VERSION 5.7 ;
  NOWIREEXTENSIONATPIN ON ;
  DIVIDERCHAR "/" ;
  BUSBITCHARS "[]" ;
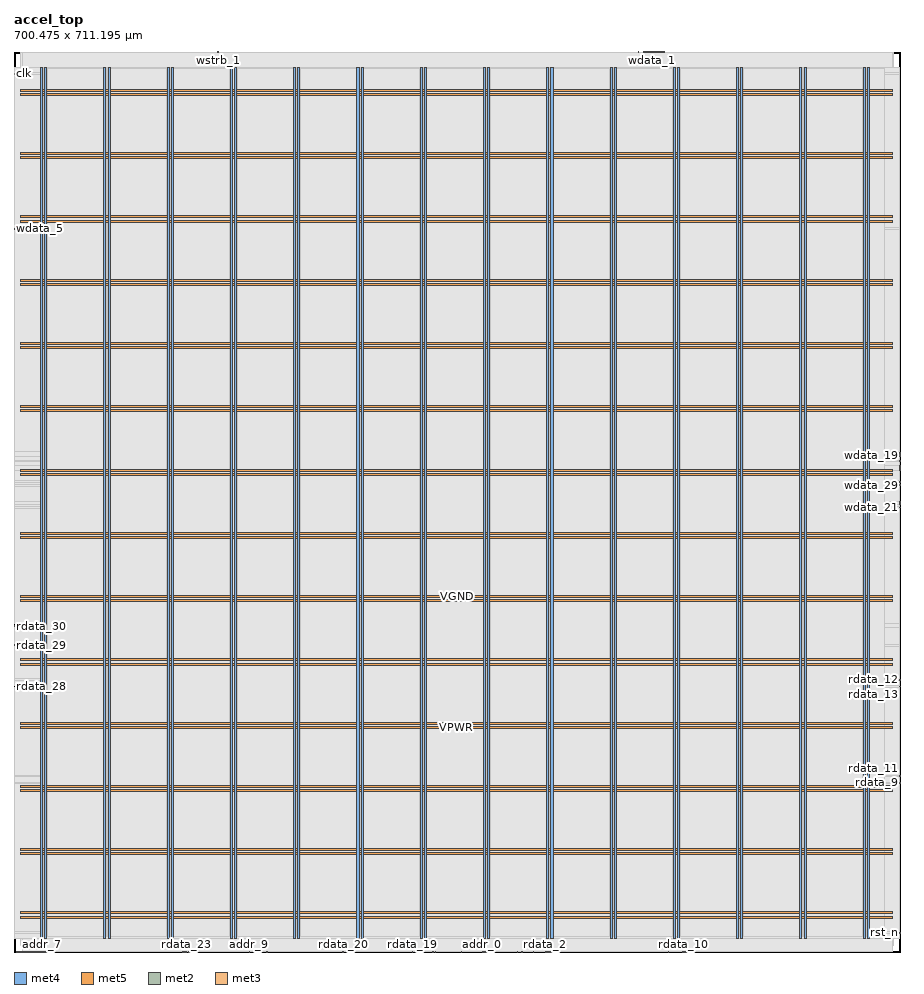
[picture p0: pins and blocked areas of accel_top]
MACRO accel_top
  CLASS BLOCK ;
  FOREIGN accel_top ;
  ORIGIN 0.000 0.000 ;
  SIZE 700.475 BY 711.195 ;
  PIN VGND
    DIRECTION INOUT ;
    USE GROUND ;
    PORT
      LAYER met4 ;
        RECT 24.340 10.640 25.940 699.280 ;
    END
    PORT
      LAYER met4 ;
        RECT 74.340 10.640 75.940 699.280 ;
    END
    PORT
      LAYER met4 ;
        RECT 124.340 10.640 125.940 699.280 ;
    END
    PORT
      LAYER met4 ;
        RECT 174.340 10.640 175.940 699.280 ;
    END
    PORT
      LAYER met4 ;
        RECT 224.340 10.640 225.940 699.280 ;
    END
    PORT
      LAYER met4 ;
        RECT 274.340 10.640 275.940 699.280 ;
    END
    PORT
      LAYER met4 ;
        RECT 324.340 10.640 325.940 699.280 ;
    END
    PORT
      LAYER met4 ;
        RECT 374.340 10.640 375.940 699.280 ;
    END
    PORT
      LAYER met4 ;
        RECT 424.340 10.640 425.940 699.280 ;
    END
    PORT
      LAYER met4 ;
        RECT 474.340 10.640 475.940 699.280 ;
    END
    PORT
      LAYER met4 ;
        RECT 524.340 10.640 525.940 699.280 ;
    END
    PORT
      LAYER met4 ;
        RECT 574.340 10.640 575.940 699.280 ;
    END
    PORT
      LAYER met4 ;
        RECT 624.340 10.640 625.940 699.280 ;
    END
    PORT
      LAYER met4 ;
        RECT 674.340 10.640 675.940 699.280 ;
    END
    PORT
      LAYER met5 ;
        RECT 5.520 30.030 694.600 31.630 ;
    END
    PORT
      LAYER met5 ;
        RECT 5.520 80.030 694.600 81.630 ;
    END
    PORT
      LAYER met5 ;
        RECT 5.520 130.030 694.600 131.630 ;
    END
    PORT
      LAYER met5 ;
        RECT 5.520 180.030 694.600 181.630 ;
    END
    PORT
      LAYER met5 ;
        RECT 5.520 230.030 694.600 231.630 ;
    END
    PORT
      LAYER met5 ;
        RECT 5.520 280.030 694.600 281.630 ;
    END
    PORT
      LAYER met5 ;
        RECT 5.520 330.030 694.600 331.630 ;
    END
    PORT
      LAYER met5 ;
        RECT 5.520 380.030 694.600 381.630 ;
    END
    PORT
      LAYER met5 ;
        RECT 5.520 430.030 694.600 431.630 ;
    END
    PORT
      LAYER met5 ;
        RECT 5.520 480.030 694.600 481.630 ;
    END
    PORT
      LAYER met5 ;
        RECT 5.520 530.030 694.600 531.630 ;
    END
    PORT
      LAYER met5 ;
        RECT 5.520 580.030 694.600 581.630 ;
    END
    PORT
      LAYER met5 ;
        RECT 5.520 630.030 694.600 631.630 ;
    END
    PORT
      LAYER met5 ;
        RECT 5.520 680.030 694.600 681.630 ;
    END
  END VGND
  PIN VPWR
    DIRECTION INOUT ;
    USE POWER ;
    PORT
      LAYER met4 ;
        RECT 21.040 10.640 22.640 699.280 ;
    END
    PORT
      LAYER met4 ;
        RECT 71.040 10.640 72.640 699.280 ;
    END
    PORT
      LAYER met4 ;
        RECT 121.040 10.640 122.640 699.280 ;
    END
    PORT
      LAYER met4 ;
        RECT 171.040 10.640 172.640 699.280 ;
    END
    PORT
      LAYER met4 ;
        RECT 221.040 10.640 222.640 699.280 ;
    END
    PORT
      LAYER met4 ;
        RECT 271.040 10.640 272.640 699.280 ;
    END
    PORT
      LAYER met4 ;
        RECT 321.040 10.640 322.640 699.280 ;
    END
    PORT
      LAYER met4 ;
        RECT 371.040 10.640 372.640 699.280 ;
    END
    PORT
      LAYER met4 ;
        RECT 421.040 10.640 422.640 699.280 ;
    END
    PORT
      LAYER met4 ;
        RECT 471.040 10.640 472.640 699.280 ;
    END
    PORT
      LAYER met4 ;
        RECT 521.040 10.640 522.640 699.280 ;
    END
    PORT
      LAYER met4 ;
        RECT 571.040 10.640 572.640 699.280 ;
    END
    PORT
      LAYER met4 ;
        RECT 621.040 10.640 622.640 699.280 ;
    END
    PORT
      LAYER met4 ;
        RECT 671.040 10.640 672.640 699.280 ;
    END
    PORT
      LAYER met5 ;
        RECT 5.520 26.730 694.600 28.330 ;
    END
    PORT
      LAYER met5 ;
        RECT 5.520 76.730 694.600 78.330 ;
    END
    PORT
      LAYER met5 ;
        RECT 5.520 126.730 694.600 128.330 ;
    END
    PORT
      LAYER met5 ;
        RECT 5.520 176.730 694.600 178.330 ;
    END
    PORT
      LAYER met5 ;
        RECT 5.520 226.730 694.600 228.330 ;
    END
    PORT
      LAYER met5 ;
        RECT 5.520 276.730 694.600 278.330 ;
    END
    PORT
      LAYER met5 ;
        RECT 5.520 326.730 694.600 328.330 ;
    END
    PORT
      LAYER met5 ;
        RECT 5.520 376.730 694.600 378.330 ;
    END
    PORT
      LAYER met5 ;
        RECT 5.520 426.730 694.600 428.330 ;
    END
    PORT
      LAYER met5 ;
        RECT 5.520 476.730 694.600 478.330 ;
    END
    PORT
      LAYER met5 ;
        RECT 5.520 526.730 694.600 528.330 ;
    END
    PORT
      LAYER met5 ;
        RECT 5.520 576.730 694.600 578.330 ;
    END
    PORT
      LAYER met5 ;
        RECT 5.520 626.730 694.600 628.330 ;
    END
    PORT
      LAYER met5 ;
        RECT 5.520 676.730 694.600 678.330 ;
    END
  END VPWR
  PIN addr_0
    DIRECTION INPUT ;
    USE SIGNAL ;
    ANTENNAGATEAREA 1.424700 ;
    ANTENNADIFFAREA 0.434700 ;
    PORT
      LAYER met2 ;
        RECT 369.930 0.000 370.210 0.280 ;
    END
  END addr_0
  PIN addr_1
    DIRECTION INPUT ;
    USE SIGNAL ;
    ANTENNAGATEAREA 0.929700 ;
    ANTENNADIFFAREA 0.434700 ;
    PORT
      LAYER met2 ;
        RECT 370.850 0.000 371.130 0.280 ;
    END
  END addr_1
  PIN addr_10
    DIRECTION INPUT ;
    USE SIGNAL ;
    ANTENNAGATEAREA 0.647700 ;
    ANTENNADIFFAREA 0.434700 ;
    PORT
      LAYER met2 ;
        RECT 371.770 0.000 372.050 0.280 ;
    END
  END addr_10
  PIN addr_11
    DIRECTION INPUT ;
    USE SIGNAL ;
    ANTENNAGATEAREA 0.647700 ;
    ANTENNADIFFAREA 0.434700 ;
    PORT
      LAYER met2 ;
        RECT 372.690 0.000 372.970 0.280 ;
    END
  END addr_11
  PIN addr_12
    DIRECTION INPUT ;
    USE SIGNAL ;
    PORT
      LAYER met2 ;
        RECT 1.930 0.000 2.210 0.280 ;
    END
  END addr_12
  PIN addr_13
    DIRECTION INPUT ;
    USE SIGNAL ;
    PORT
      LAYER met2 ;
        RECT 2.850 0.000 3.130 0.280 ;
    END
  END addr_13
  PIN addr_14
    DIRECTION INPUT ;
    USE SIGNAL ;
    PORT
      LAYER met2 ;
        RECT 3.770 0.000 4.050 0.280 ;
    END
  END addr_14
  PIN addr_15
    DIRECTION INPUT ;
    USE SIGNAL ;
    PORT
      LAYER met2 ;
        RECT 4.690 0.000 4.970 0.280 ;
    END
  END addr_15
  PIN addr_16
    DIRECTION INPUT ;
    USE SIGNAL ;
    PORT
      LAYER met2 ;
        RECT 5.610 0.000 5.890 0.280 ;
    END
  END addr_16
  PIN addr_17
    DIRECTION INPUT ;
    USE SIGNAL ;
    PORT
      LAYER met2 ;
        RECT 6.530 0.000 6.810 0.280 ;
    END
  END addr_17
  PIN addr_18
    DIRECTION INPUT ;
    USE SIGNAL ;
    PORT
      LAYER met2 ;
        RECT 7.450 0.000 7.730 0.280 ;
    END
  END addr_18
  PIN addr_19
    DIRECTION INPUT ;
    USE SIGNAL ;
    PORT
      LAYER met2 ;
        RECT 8.370 0.000 8.650 0.280 ;
    END
  END addr_19
  PIN addr_2
    DIRECTION INPUT ;
    USE SIGNAL ;
    ANTENNAGATEAREA 1.177200 ;
    ANTENNADIFFAREA 0.434700 ;
    PORT
      LAYER met2 ;
        RECT 373.610 0.000 373.890 0.280 ;
    END
  END addr_2
  PIN addr_20
    DIRECTION INPUT ;
    USE SIGNAL ;
    PORT
      LAYER met2 ;
        RECT 9.290 0.000 9.570 0.280 ;
    END
  END addr_20
  PIN addr_21
    DIRECTION INPUT ;
    USE SIGNAL ;
    PORT
      LAYER met2 ;
        RECT 10.210 0.000 10.490 0.280 ;
    END
  END addr_21
  PIN addr_22
    DIRECTION INPUT ;
    USE SIGNAL ;
    PORT
      LAYER met2 ;
        RECT 11.130 0.000 11.410 0.280 ;
    END
  END addr_22
  PIN addr_23
    DIRECTION INPUT ;
    USE SIGNAL ;
    PORT
      LAYER met2 ;
        RECT 12.050 0.000 12.330 0.280 ;
    END
  END addr_23
  PIN addr_24
    DIRECTION INPUT ;
    USE SIGNAL ;
    PORT
      LAYER met2 ;
        RECT 12.970 0.000 13.250 0.280 ;
    END
  END addr_24
  PIN addr_25
    DIRECTION INPUT ;
    USE SIGNAL ;
    PORT
      LAYER met2 ;
        RECT 13.890 0.000 14.170 0.280 ;
    END
  END addr_25
  PIN addr_26
    DIRECTION INPUT ;
    USE SIGNAL ;
    PORT
      LAYER met2 ;
        RECT 14.810 0.000 15.090 0.280 ;
    END
  END addr_26
  PIN addr_27
    DIRECTION INPUT ;
    USE SIGNAL ;
    PORT
      LAYER met2 ;
        RECT 15.730 0.000 16.010 0.280 ;
    END
  END addr_27
  PIN addr_28
    DIRECTION INPUT ;
    USE SIGNAL ;
    PORT
      LAYER met2 ;
        RECT 16.650 0.000 16.930 0.280 ;
    END
  END addr_28
  PIN addr_29
    DIRECTION INPUT ;
    USE SIGNAL ;
    PORT
      LAYER met2 ;
        RECT 17.570 0.000 17.850 0.280 ;
    END
  END addr_29
  PIN addr_3
    DIRECTION INPUT ;
    USE SIGNAL ;
    ANTENNAGATEAREA 0.647700 ;
    ANTENNADIFFAREA 0.434700 ;
    PORT
      LAYER met2 ;
        RECT 374.530 0.000 374.810 0.280 ;
    END
  END addr_3
  PIN addr_30
    DIRECTION INPUT ;
    USE SIGNAL ;
    PORT
      LAYER met2 ;
        RECT 18.490 0.000 18.770 0.280 ;
    END
  END addr_30
  PIN addr_31
    DIRECTION INPUT ;
    USE SIGNAL ;
    PORT
      LAYER met2 ;
        RECT 19.410 0.000 19.690 0.280 ;
    END
  END addr_31
  PIN addr_4
    DIRECTION INPUT ;
    USE SIGNAL ;
    ANTENNAGATEAREA 0.929700 ;
    ANTENNADIFFAREA 0.434700 ;
    PORT
      LAYER met2 ;
        RECT 375.450 0.000 375.730 0.280 ;
    END
  END addr_4
  PIN addr_5
    DIRECTION INPUT ;
    USE SIGNAL ;
    PORT
      LAYER met2 ;
        RECT 20.330 0.000 20.610 0.280 ;
    END
  END addr_5
  PIN addr_6
    DIRECTION INPUT ;
    USE SIGNAL ;
    PORT
      LAYER met2 ;
        RECT 21.250 0.000 21.530 0.280 ;
    END
  END addr_6
  PIN addr_7
    DIRECTION INPUT ;
    USE SIGNAL ;
    PORT
      LAYER met2 ;
        RECT 22.170 0.000 22.450 0.280 ;
    END
  END addr_7
  PIN addr_8
    DIRECTION INPUT ;
    USE SIGNAL ;
    PORT
      LAYER met2 ;
        RECT 23.090 0.000 23.370 0.280 ;
    END
  END addr_8
  PIN addr_9
    DIRECTION INPUT ;
    USE SIGNAL ;
    ANTENNAGATEAREA 1.424700 ;
    ANTENNADIFFAREA 0.434700 ;
    PORT
      LAYER met2 ;
        RECT 185.930 0.000 186.210 0.280 ;
    END
  END addr_9
  PIN clk
    DIRECTION INPUT ;
    USE SIGNAL ;
    ANTENNAGATEAREA 1.286700 ;
    ANTENNADIFFAREA 0.434700 ;
    PORT
      LAYER met3 ;
        RECT 0.000 693.640 0.600 694.240 ;
    END
  END clk
  PIN irq
    DIRECTION OUTPUT ;
    USE SIGNAL ;
    ANTENNAGATEAREA 0.560700 ;
    ANTENNADIFFAREA 0.863700 ;
    PORT
      LAYER met2 ;
        RECT 420.530 0.000 420.810 0.280 ;
    END
  END irq
  PIN rdata_0
    DIRECTION OUTPUT ;
    USE SIGNAL ;
    ANTENNAGATEAREA 0.434700 ;
    ANTENNADIFFAREA 1.771200 ;
    PORT
      LAYER met2 ;
        RECT 401.210 0.000 401.490 0.280 ;
    END
  END rdata_0
  PIN rdata_1
    DIRECTION OUTPUT ;
    USE SIGNAL ;
    ANTENNAGATEAREA 0.434700 ;
    ANTENNADIFFAREA 2.216700 ;
    PORT
      LAYER met2 ;
        RECT 424.210 0.000 424.490 0.280 ;
    END
  END rdata_1
  PIN rdata_10
    DIRECTION OUTPUT ;
    USE SIGNAL ;
    ANTENNAGATEAREA 0.434700 ;
    ANTENNADIFFAREA 2.216700 ;
    PORT
      LAYER met2 ;
        RECT 529.090 0.000 529.370 0.280 ;
    END
  END rdata_10
  PIN rdata_11
    DIRECTION OUTPUT ;
    USE SIGNAL ;
    ANTENNAGATEAREA 0.434700 ;
    ANTENNADIFFAREA 2.216700 ;
    PORT
      LAYER met3 ;
        RECT 699.875 138.760 700.475 139.360 ;
    END
  END rdata_11
  PIN rdata_12
    DIRECTION OUTPUT ;
    USE SIGNAL ;
    ANTENNAGATEAREA 0.434700 ;
    ANTENNADIFFAREA 2.216700 ;
    PORT
      LAYER met3 ;
        RECT 699.875 214.920 700.475 215.520 ;
    END
  END rdata_12
  PIN rdata_13
    DIRECTION OUTPUT ;
    USE SIGNAL ;
    ANTENNAGATEAREA 0.434700 ;
    ANTENNADIFFAREA 2.216700 ;
    PORT
      LAYER met3 ;
        RECT 699.875 209.480 700.475 210.080 ;
    END
  END rdata_13
  PIN rdata_14
    DIRECTION OUTPUT ;
    USE SIGNAL ;
    ANTENNAGATEAREA 0.434700 ;
    ANTENNADIFFAREA 1.771200 ;
    PORT
      LAYER met2 ;
        RECT 377.290 0.000 377.570 0.280 ;
    END
  END rdata_14
  PIN rdata_15
    DIRECTION OUTPUT ;
    USE SIGNAL ;
    ANTENNAGATEAREA 0.434700 ;
    ANTENNADIFFAREA 2.216700 ;
    PORT
      LAYER met2 ;
        RECT 333.130 0.000 333.410 0.280 ;
    END
  END rdata_15
  PIN rdata_16
    DIRECTION OUTPUT ;
    USE SIGNAL ;
    ANTENNAGATEAREA 0.434700 ;
    ANTENNADIFFAREA 1.771200 ;
    PORT
      LAYER met2 ;
        RECT 397.530 0.000 397.810 0.280 ;
    END
  END rdata_16
  PIN rdata_17
    DIRECTION OUTPUT ;
    USE SIGNAL ;
    ANTENNAGATEAREA 0.434700 ;
    ANTENNADIFFAREA 1.771200 ;
    PORT
      LAYER met2 ;
        RECT 421.450 0.000 421.730 0.280 ;
    END
  END rdata_17
  PIN rdata_18
    DIRECTION OUTPUT ;
    USE SIGNAL ;
    ANTENNAGATEAREA 0.434700 ;
    ANTENNADIFFAREA 2.216700 ;
    PORT
      LAYER met2 ;
        RECT 353.370 0.000 353.650 0.280 ;
    END
  END rdata_18
  PIN rdata_19
    DIRECTION OUTPUT ;
    USE SIGNAL ;
    ANTENNAGATEAREA 0.434700 ;
    ANTENNADIFFAREA 2.216700 ;
    PORT
      LAYER met2 ;
        RECT 314.730 0.000 315.010 0.280 ;
    END
  END rdata_19
  PIN rdata_2
    DIRECTION OUTPUT ;
    USE SIGNAL ;
    ANTENNAGATEAREA 0.434700 ;
    ANTENNADIFFAREA 2.216700 ;
    PORT
      LAYER met2 ;
        RECT 419.610 0.000 419.890 0.280 ;
    END
  END rdata_2
  PIN rdata_20
    DIRECTION OUTPUT ;
    USE SIGNAL ;
    ANTENNAGATEAREA 0.434700 ;
    ANTENNADIFFAREA 1.325700 ;
    PORT
      LAYER met2 ;
        RECT 260.450 0.000 260.730 0.280 ;
    END
  END rdata_20
  PIN rdata_21
    DIRECTION OUTPUT ;
    USE SIGNAL ;
    ANTENNAGATEAREA 0.434700 ;
    ANTENNADIFFAREA 2.216700 ;
    PORT
      LAYER met2 ;
        RECT 259.530 0.000 259.810 0.280 ;
    END
  END rdata_21
  PIN rdata_22
    DIRECTION OUTPUT ;
    USE SIGNAL ;
    ANTENNAGATEAREA 0.434700 ;
    ANTENNADIFFAREA 2.216700 ;
    PORT
      LAYER met2 ;
        RECT 199.730 0.000 200.010 0.280 ;
    END
  END rdata_22
  PIN rdata_23
    DIRECTION OUTPUT ;
    USE SIGNAL ;
    ANTENNAGATEAREA 0.434700 ;
    ANTENNADIFFAREA 2.216700 ;
    PORT
      LAYER met2 ;
        RECT 136.250 0.000 136.530 0.280 ;
    END
  END rdata_23
  PIN rdata_24
    DIRECTION OUTPUT ;
    USE SIGNAL ;
    ANTENNAGATEAREA 0.434700 ;
    ANTENNADIFFAREA 2.216700 ;
    PORT
      LAYER met2 ;
        RECT 135.330 0.000 135.610 0.280 ;
    END
  END rdata_24
  PIN rdata_25
    DIRECTION OUTPUT ;
    USE SIGNAL ;
    ANTENNAGATEAREA 0.434700 ;
    ANTENNADIFFAREA 2.216700 ;
    PORT
      LAYER met2 ;
        RECT 133.490 0.000 133.770 0.280 ;
    END
  END rdata_25
  PIN rdata_26
    DIRECTION OUTPUT ;
    USE SIGNAL ;
    ANTENNAGATEAREA 0.434700 ;
    ANTENNADIFFAREA 2.216700 ;
    PORT
      LAYER met2 ;
        RECT 138.090 0.000 138.370 0.280 ;
    END
  END rdata_26
  PIN rdata_27
    DIRECTION OUTPUT ;
    USE SIGNAL ;
    ANTENNAGATEAREA 0.434700 ;
    ANTENNADIFFAREA 2.216700 ;
    PORT
      LAYER met2 ;
        RECT 134.410 0.000 134.690 0.280 ;
    END
  END rdata_27
  PIN rdata_28
    DIRECTION OUTPUT ;
    USE SIGNAL ;
    ANTENNAGATEAREA 0.434700 ;
    ANTENNADIFFAREA 1.771200 ;
    PORT
      LAYER met3 ;
        RECT 0.000 209.480 0.600 210.080 ;
    END
  END rdata_28
  PIN rdata_29
    DIRECTION OUTPUT ;
    USE SIGNAL ;
    ANTENNAGATEAREA 0.434700 ;
    ANTENNADIFFAREA 1.771200 ;
    PORT
      LAYER met3 ;
        RECT 0.000 242.120 0.600 242.720 ;
    END
  END rdata_29
  PIN rdata_3
    DIRECTION OUTPUT ;
    USE SIGNAL ;
    ANTENNAGATEAREA 0.434700 ;
    ANTENNADIFFAREA 2.216700 ;
    PORT
      LAYER met2 ;
        RECT 422.370 0.000 422.650 0.280 ;
    END
  END rdata_3
  PIN rdata_30
    DIRECTION OUTPUT ;
    USE SIGNAL ;
    ANTENNAGATEAREA 0.434700 ;
    ANTENNADIFFAREA 1.771200 ;
    PORT
      LAYER met3 ;
        RECT 0.000 257.080 0.600 257.680 ;
    END
  END rdata_30
  PIN rdata_31
    DIRECTION OUTPUT ;
    USE SIGNAL ;
    ANTENNAGATEAREA 0.434700 ;
    ANTENNADIFFAREA 2.216700 ;
    PORT
      LAYER met3 ;
        RECT 0.000 258.440 0.600 259.040 ;
    END
  END rdata_31
  PIN rdata_4
    DIRECTION OUTPUT ;
    USE SIGNAL ;
    ANTENNAGATEAREA 0.434700 ;
    ANTENNADIFFAREA 1.771200 ;
    PORT
      LAYER met2 ;
        RECT 410.410 0.000 410.690 0.280 ;
    END
  END rdata_4
  PIN rdata_5
    DIRECTION OUTPUT ;
    USE SIGNAL ;
    ANTENNAGATEAREA 0.434700 ;
    ANTENNADIFFAREA 2.216700 ;
    PORT
      LAYER met2 ;
        RECT 517.130 0.000 517.410 0.280 ;
    END
  END rdata_5
  PIN rdata_6
    DIRECTION OUTPUT ;
    USE SIGNAL ;
    ANTENNAGATEAREA 0.434700 ;
    ANTENNADIFFAREA 2.216700 ;
    PORT
      LAYER met2 ;
        RECT 528.170 0.000 528.450 0.280 ;
    END
  END rdata_6
  PIN rdata_7
    DIRECTION OUTPUT ;
    USE SIGNAL ;
    ANTENNAGATEAREA 0.434700 ;
    ANTENNADIFFAREA 1.771200 ;
    PORT
      LAYER met2 ;
        RECT 530.010 0.000 530.290 0.280 ;
    END
  END rdata_7
  PIN rdata_8
    DIRECTION OUTPUT ;
    USE SIGNAL ;
    ANTENNAGATEAREA 0.434700 ;
    ANTENNADIFFAREA 1.771200 ;
    PORT
      LAYER met2 ;
        RECT 423.290 0.000 423.570 0.280 ;
    END
  END rdata_8
  PIN rdata_9
    DIRECTION OUTPUT ;
    USE SIGNAL ;
    ANTENNAGATEAREA 0.434700 ;
    ANTENNADIFFAREA 2.216700 ;
    PORT
      LAYER met3 ;
        RECT 699.875 133.320 700.475 133.920 ;
    END
  END rdata_9
  PIN ready
    DIRECTION OUTPUT ;
    USE SIGNAL ;
    ANTENNAGATEAREA 0.434700 ;
    ANTENNADIFFAREA 1.137600 ;
    PORT
      LAYER met2 ;
        RECT 331.290 0.000 331.570 0.280 ;
    END
  END ready
  PIN req
    DIRECTION INPUT ;
    USE SIGNAL ;
    ANTENNAGATEAREA 0.647700 ;
    ANTENNADIFFAREA 0.434700 ;
    PORT
      LAYER met2 ;
        RECT 330.370 0.000 330.650 0.280 ;
    END
  END req
  PIN rst_n
    DIRECTION INPUT ;
    USE SIGNAL ;
    ANTENNAGATEAREA 0.647700 ;
    ANTENNADIFFAREA 0.434700 ;
    PORT
      LAYER met3 ;
        RECT 699.875 15.000 700.475 15.600 ;
    END
  END rst_n
  PIN wdata_0
    DIRECTION INPUT ;
    USE SIGNAL ;
    ANTENNAGATEAREA 0.593700 ;
    ANTENNADIFFAREA 0.434700 ;
    PORT
      LAYER met2 ;
        RECT 503.330 710.915 503.610 711.195 ;
    END
  END wdata_0
  PIN wdata_1
    DIRECTION INPUT ;
    USE SIGNAL ;
    ANTENNAGATEAREA 0.593700 ;
    ANTENNADIFFAREA 0.434700 ;
    PORT
      LAYER met2 ;
        RECT 504.250 710.915 504.530 711.195 ;
    END
  END wdata_1
  PIN wdata_10
    DIRECTION INPUT ;
    USE SIGNAL ;
    ANTENNAGATEAREA 0.593700 ;
    ANTENNADIFFAREA 0.434700 ;
    PORT
      LAYER met2 ;
        RECT 513.450 710.915 513.730 711.195 ;
    END
  END wdata_10
  PIN wdata_11
    DIRECTION INPUT ;
    USE SIGNAL ;
    ANTENNAGATEAREA 0.593700 ;
    ANTENNADIFFAREA 0.434700 ;
    PORT
      LAYER met2 ;
        RECT 512.530 710.915 512.810 711.195 ;
    END
  END wdata_11
  PIN wdata_12
    DIRECTION INPUT ;
    USE SIGNAL ;
    ANTENNAGATEAREA 0.593700 ;
    ANTENNADIFFAREA 0.434700 ;
    PORT
      LAYER met2 ;
        RECT 511.610 710.915 511.890 711.195 ;
    END
  END wdata_12
  PIN wdata_13
    DIRECTION INPUT ;
    USE SIGNAL ;
    ANTENNAGATEAREA 0.593700 ;
    ANTENNADIFFAREA 0.434700 ;
    PORT
      LAYER met2 ;
        RECT 510.690 710.915 510.970 711.195 ;
    END
  END wdata_13
  PIN wdata_14
    DIRECTION INPUT ;
    USE SIGNAL ;
    ANTENNAGATEAREA 0.593700 ;
    ANTENNADIFFAREA 0.434700 ;
    PORT
      LAYER met2 ;
        RECT 509.770 710.915 510.050 711.195 ;
    END
  END wdata_14
  PIN wdata_15
    DIRECTION INPUT ;
    USE SIGNAL ;
    ANTENNAGATEAREA 0.593700 ;
    ANTENNADIFFAREA 0.434700 ;
    PORT
      LAYER met2 ;
        RECT 508.850 710.915 509.130 711.195 ;
    END
  END wdata_15
  PIN wdata_16
    DIRECTION INPUT ;
    USE SIGNAL ;
    ANTENNAGATEAREA 0.593700 ;
    ANTENNADIFFAREA 0.434700 ;
    PORT
      LAYER met3 ;
        RECT 699.875 383.560 700.475 384.160 ;
    END
  END wdata_16
  PIN wdata_17
    DIRECTION INPUT ;
    USE SIGNAL ;
    ANTENNAGATEAREA 0.593700 ;
    ANTENNADIFFAREA 0.434700 ;
    PORT
      LAYER met3 ;
        RECT 699.875 393.080 700.475 393.680 ;
    END
  END wdata_17
  PIN wdata_18
    DIRECTION INPUT ;
    USE SIGNAL ;
    ANTENNAGATEAREA 0.593700 ;
    ANTENNADIFFAREA 0.434700 ;
    PORT
      LAYER met3 ;
        RECT 699.875 382.200 700.475 382.800 ;
    END
  END wdata_18
  PIN wdata_19
    DIRECTION INPUT ;
    USE SIGNAL ;
    ANTENNAGATEAREA 0.593700 ;
    ANTENNADIFFAREA 0.434700 ;
    PORT
      LAYER met3 ;
        RECT 699.875 391.720 700.475 392.320 ;
    END
  END wdata_19
  PIN wdata_2
    DIRECTION INPUT ;
    USE SIGNAL ;
    ANTENNAGATEAREA 0.593700 ;
    ANTENNADIFFAREA 0.434700 ;
    PORT
      LAYER met2 ;
        RECT 507.930 710.915 508.210 711.195 ;
    END
  END wdata_2
  PIN wdata_20
    DIRECTION INPUT ;
    USE SIGNAL ;
    ANTENNAGATEAREA 0.593700 ;
    ANTENNADIFFAREA 0.434700 ;
    PORT
      LAYER met3 ;
        RECT 699.875 353.640 700.475 354.240 ;
    END
  END wdata_20
  PIN wdata_21
    DIRECTION INPUT ;
    USE SIGNAL ;
    ANTENNAGATEAREA 0.593700 ;
    ANTENNADIFFAREA 0.434700 ;
    PORT
      LAYER met3 ;
        RECT 699.875 350.920 700.475 351.520 ;
    END
  END wdata_21
  PIN wdata_22
    DIRECTION INPUT ;
    USE SIGNAL ;
    ANTENNAGATEAREA 0.593700 ;
    ANTENNADIFFAREA 0.434700 ;
    PORT
      LAYER met2 ;
        RECT 507.010 710.915 507.290 711.195 ;
    END
  END wdata_22
  PIN wdata_23
    DIRECTION INPUT ;
    USE SIGNAL ;
    ANTENNAGATEAREA 0.593700 ;
    ANTENNADIFFAREA 0.434700 ;
    PORT
      LAYER met3 ;
        RECT 699.875 355.000 700.475 355.600 ;
    END
  END wdata_23
  PIN wdata_24
    DIRECTION INPUT ;
    USE SIGNAL ;
    ANTENNAGATEAREA 0.593700 ;
    ANTENNADIFFAREA 0.434700 ;
    PORT
      LAYER met2 ;
        RECT 506.090 710.915 506.370 711.195 ;
    END
  END wdata_24
  PIN wdata_25
    DIRECTION INPUT ;
    USE SIGNAL ;
    ANTENNAGATEAREA 0.593700 ;
    ANTENNADIFFAREA 0.434700 ;
    PORT
      LAYER met3 ;
        RECT 699.875 371.320 700.475 371.920 ;
    END
  END wdata_25
  PIN wdata_26
    DIRECTION INPUT ;
    USE SIGNAL ;
    ANTENNAGATEAREA 0.593700 ;
    ANTENNADIFFAREA 0.434700 ;
    PORT
      LAYER met3 ;
        RECT 699.875 394.440 700.475 395.040 ;
    END
  END wdata_26
  PIN wdata_27
    DIRECTION INPUT ;
    USE SIGNAL ;
    ANTENNAGATEAREA 0.593700 ;
    ANTENNADIFFAREA 0.434700 ;
    PORT
      LAYER met3 ;
        RECT 699.875 380.840 700.475 381.440 ;
    END
  END wdata_27
  PIN wdata_28
    DIRECTION INPUT ;
    USE SIGNAL ;
    ANTENNAGATEAREA 0.593700 ;
    ANTENNADIFFAREA 0.434700 ;
    PORT
      LAYER met2 ;
        RECT 505.170 710.915 505.450 711.195 ;
    END
  END wdata_28
  PIN wdata_29
    DIRECTION INPUT ;
    USE SIGNAL ;
    ANTENNAGATEAREA 0.593700 ;
    ANTENNADIFFAREA 0.434700 ;
    PORT
      LAYER met3 ;
        RECT 699.875 368.600 700.475 369.200 ;
    END
  END wdata_29
  PIN wdata_3
    DIRECTION INPUT ;
    USE SIGNAL ;
    ANTENNAGATEAREA 0.593700 ;
    ANTENNADIFFAREA 0.434700 ;
    PORT
      LAYER met2 ;
        RECT 502.410 710.915 502.690 711.195 ;
    END
  END wdata_3
  PIN wdata_30
    DIRECTION INPUT ;
    USE SIGNAL ;
    ANTENNAGATEAREA 0.593700 ;
    ANTENNADIFFAREA 0.434700 ;
    PORT
      LAYER met3 ;
        RECT 699.875 387.640 700.475 388.240 ;
    END
  END wdata_30
  PIN wdata_31
    DIRECTION INPUT ;
    USE SIGNAL ;
    ANTENNAGATEAREA 0.647700 ;
    ANTENNADIFFAREA 0.434700 ;
    PORT
      LAYER met2 ;
        RECT 501.490 710.915 501.770 711.195 ;
    END
  END wdata_31
  PIN wdata_4
    DIRECTION INPUT ;
    USE SIGNAL ;
    ANTENNAGATEAREA 0.593700 ;
    ANTENNADIFFAREA 0.434700 ;
    PORT
      LAYER met2 ;
        RECT 493.210 710.915 493.490 711.195 ;
    END
  END wdata_4
  PIN wdata_5
    DIRECTION INPUT ;
    USE SIGNAL ;
    ANTENNAGATEAREA 0.593700 ;
    ANTENNADIFFAREA 0.434700 ;
    PORT
      LAYER met3 ;
        RECT 0.000 571.240 0.600 571.840 ;
    END
  END wdata_5
  PIN wdata_6
    DIRECTION INPUT ;
    USE SIGNAL ;
    ANTENNAGATEAREA 0.593700 ;
    ANTENNADIFFAREA 0.434700 ;
    PORT
      LAYER met2 ;
        RECT 500.570 710.915 500.850 711.195 ;
    END
  END wdata_6
  PIN wdata_7
    DIRECTION INPUT ;
    USE SIGNAL ;
    ANTENNAGATEAREA 0.593700 ;
    ANTENNADIFFAREA 0.434700 ;
    PORT
      LAYER met2 ;
        RECT 499.650 710.915 499.930 711.195 ;
    END
  END wdata_7
  PIN wdata_8
    DIRECTION INPUT ;
    USE SIGNAL ;
    ANTENNAGATEAREA 0.593700 ;
    ANTENNADIFFAREA 0.434700 ;
    PORT
      LAYER met2 ;
        RECT 498.730 710.915 499.010 711.195 ;
    END
  END wdata_8
  PIN wdata_9
    DIRECTION INPUT ;
    USE SIGNAL ;
    ANTENNAGATEAREA 0.593700 ;
    ANTENNADIFFAREA 0.434700 ;
    PORT
      LAYER met2 ;
        RECT 497.810 710.915 498.090 711.195 ;
    END
  END wdata_9
  PIN wstrb_0
    DIRECTION INPUT ;
    USE SIGNAL ;
    PORT
      LAYER met2 ;
        RECT 24.010 0.000 24.290 0.280 ;
    END
  END wstrb_0
  PIN wstrb_1
    DIRECTION INPUT ;
    USE SIGNAL ;
    ANTENNAGATEAREA 0.631200 ;
    ANTENNADIFFAREA 0.434700 ;
    PORT
      LAYER met2 ;
        RECT 161.090 710.915 161.370 711.195 ;
    END
  END wstrb_1
  PIN wstrb_2
    DIRECTION INPUT ;
    USE SIGNAL ;
    PORT
      LAYER met2 ;
        RECT 24.930 0.000 25.210 0.280 ;
    END
  END wstrb_2
  PIN wstrb_3
    DIRECTION INPUT ;
    USE SIGNAL ;
    PORT
      LAYER met2 ;
        RECT 25.850 0.000 26.130 0.280 ;
    END
  END wstrb_3
  OBS
      LAYER nwell ;
        RECT 5.330 10.795 694.790 699.230 ;
      LAYER li1 ;
        RECT 5.520 10.795 694.600 699.125 ;
      LAYER met1 ;
        RECT 5.520 5.480 694.900 710.900 ;
      LAYER met2 ;
        RECT 6.530 710.635 160.810 710.930 ;
        RECT 161.650 710.635 492.930 710.930 ;
        RECT 493.770 710.635 497.530 710.930 ;
        RECT 498.370 710.635 498.450 710.930 ;
        RECT 499.290 710.635 499.370 710.930 ;
        RECT 500.210 710.635 500.290 710.930 ;
        RECT 501.130 710.635 501.210 710.930 ;
        RECT 502.050 710.635 502.130 710.930 ;
        RECT 502.970 710.635 503.050 710.930 ;
        RECT 503.890 710.635 503.970 710.930 ;
        RECT 504.810 710.635 504.890 710.930 ;
        RECT 505.730 710.635 505.810 710.930 ;
        RECT 506.650 710.635 506.730 710.930 ;
        RECT 507.570 710.635 507.650 710.930 ;
        RECT 508.490 710.635 508.570 710.930 ;
        RECT 509.410 710.635 509.490 710.930 ;
        RECT 510.330 710.635 510.410 710.930 ;
        RECT 511.250 710.635 511.330 710.930 ;
        RECT 512.170 710.635 512.250 710.930 ;
        RECT 513.090 710.635 513.170 710.930 ;
        RECT 514.010 710.635 694.510 710.930 ;
        RECT 6.530 0.560 694.510 710.635 ;
        RECT 7.090 0.070 7.170 0.560 ;
        RECT 8.010 0.070 8.090 0.560 ;
        RECT 8.930 0.070 9.010 0.560 ;
        RECT 9.850 0.070 9.930 0.560 ;
        RECT 10.770 0.070 10.850 0.560 ;
        RECT 11.690 0.070 11.770 0.560 ;
        RECT 12.610 0.070 12.690 0.560 ;
        RECT 13.530 0.070 13.610 0.560 ;
        RECT 14.450 0.070 14.530 0.560 ;
        RECT 15.370 0.070 15.450 0.560 ;
        RECT 16.290 0.070 16.370 0.560 ;
        RECT 17.210 0.070 17.290 0.560 ;
        RECT 18.130 0.070 18.210 0.560 ;
        RECT 19.050 0.070 19.130 0.560 ;
        RECT 19.970 0.070 20.050 0.560 ;
        RECT 20.890 0.070 20.970 0.560 ;
        RECT 21.810 0.070 21.890 0.560 ;
        RECT 22.730 0.070 22.810 0.560 ;
        RECT 23.650 0.070 23.730 0.560 ;
        RECT 24.570 0.070 24.650 0.560 ;
        RECT 25.490 0.070 25.570 0.560 ;
        RECT 26.410 0.070 133.210 0.560 ;
        RECT 134.050 0.070 134.130 0.560 ;
        RECT 134.970 0.070 135.050 0.560 ;
        RECT 135.890 0.070 135.970 0.560 ;
        RECT 136.810 0.070 137.810 0.560 ;
        RECT 138.650 0.070 185.650 0.560 ;
        RECT 186.490 0.070 199.450 0.560 ;
        RECT 200.290 0.070 259.250 0.560 ;
        RECT 260.090 0.070 260.170 0.560 ;
        RECT 261.010 0.070 314.450 0.560 ;
        RECT 315.290 0.070 330.090 0.560 ;
        RECT 330.930 0.070 331.010 0.560 ;
        RECT 331.850 0.070 332.850 0.560 ;
        RECT 333.690 0.070 353.090 0.560 ;
        RECT 353.930 0.070 369.650 0.560 ;
        RECT 370.490 0.070 370.570 0.560 ;
        RECT 371.410 0.070 371.490 0.560 ;
        RECT 372.330 0.070 372.410 0.560 ;
        RECT 373.250 0.070 373.330 0.560 ;
        RECT 374.170 0.070 374.250 0.560 ;
        RECT 375.090 0.070 375.170 0.560 ;
        RECT 376.010 0.070 377.010 0.560 ;
        RECT 377.850 0.070 397.250 0.560 ;
        RECT 398.090 0.070 400.930 0.560 ;
        RECT 401.770 0.070 410.130 0.560 ;
        RECT 410.970 0.070 419.330 0.560 ;
        RECT 420.170 0.070 420.250 0.560 ;
        RECT 421.090 0.070 421.170 0.560 ;
        RECT 422.010 0.070 422.090 0.560 ;
        RECT 422.930 0.070 423.010 0.560 ;
        RECT 423.850 0.070 423.930 0.560 ;
        RECT 424.770 0.070 516.850 0.560 ;
        RECT 517.690 0.070 527.890 0.560 ;
        RECT 528.730 0.070 528.810 0.560 ;
        RECT 529.650 0.070 529.730 0.560 ;
        RECT 530.570 0.070 694.510 0.560 ;
      LAYER met3 ;
        RECT 0.600 694.640 699.875 699.205 ;
        RECT 1.000 693.240 699.875 694.640 ;
        RECT 0.600 572.240 699.875 693.240 ;
        RECT 1.000 570.840 699.875 572.240 ;
        RECT 0.600 395.440 699.875 570.840 ;
        RECT 0.600 391.320 699.475 395.440 ;
        RECT 0.600 388.640 699.875 391.320 ;
        RECT 0.600 387.240 699.475 388.640 ;
        RECT 0.600 384.560 699.875 387.240 ;
        RECT 0.600 380.440 699.475 384.560 ;
        RECT 0.600 372.320 699.875 380.440 ;
        RECT 0.600 370.920 699.475 372.320 ;
        RECT 0.600 369.600 699.875 370.920 ;
        RECT 0.600 368.200 699.475 369.600 ;
        RECT 0.600 356.000 699.875 368.200 ;
        RECT 0.600 353.240 699.475 356.000 ;
        RECT 0.600 351.920 699.875 353.240 ;
        RECT 0.600 350.520 699.475 351.920 ;
        RECT 0.600 259.440 699.875 350.520 ;
        RECT 1.000 256.680 699.875 259.440 ;
        RECT 0.600 243.120 699.875 256.680 ;
        RECT 1.000 241.720 699.875 243.120 ;
        RECT 0.600 215.920 699.875 241.720 ;
        RECT 0.600 214.520 699.475 215.920 ;
        RECT 0.600 210.480 699.875 214.520 ;
        RECT 1.000 209.080 699.475 210.480 ;
        RECT 0.600 139.760 699.875 209.080 ;
        RECT 0.600 138.360 699.475 139.760 ;
        RECT 0.600 134.320 699.875 138.360 ;
        RECT 0.600 132.920 699.475 134.320 ;
        RECT 0.600 16.000 699.875 132.920 ;
        RECT 0.600 14.600 699.475 16.000 ;
        RECT 0.600 10.715 699.875 14.600 ;
      LAYER met4 ;
        RECT 23.295 12.415 23.940 698.185 ;
        RECT 26.340 12.415 70.640 698.185 ;
        RECT 73.040 12.415 73.940 698.185 ;
        RECT 76.340 12.415 120.640 698.185 ;
        RECT 123.040 12.415 123.940 698.185 ;
        RECT 126.340 12.415 170.640 698.185 ;
        RECT 173.040 12.415 173.940 698.185 ;
        RECT 176.340 12.415 220.640 698.185 ;
        RECT 223.040 12.415 223.940 698.185 ;
        RECT 226.340 12.415 270.640 698.185 ;
        RECT 273.040 12.415 273.940 698.185 ;
        RECT 276.340 12.415 320.640 698.185 ;
        RECT 323.040 12.415 323.940 698.185 ;
        RECT 326.340 12.415 370.640 698.185 ;
        RECT 373.040 12.415 373.940 698.185 ;
        RECT 376.340 12.415 420.640 698.185 ;
        RECT 423.040 12.415 423.940 698.185 ;
        RECT 426.340 12.415 470.640 698.185 ;
        RECT 473.040 12.415 473.940 698.185 ;
        RECT 476.340 12.415 520.640 698.185 ;
        RECT 523.040 12.415 523.940 698.185 ;
        RECT 526.340 12.415 570.640 698.185 ;
        RECT 573.040 12.415 573.940 698.185 ;
        RECT 576.340 12.415 620.640 698.185 ;
        RECT 623.040 12.415 623.940 698.185 ;
        RECT 626.340 12.415 670.640 698.185 ;
        RECT 673.040 12.415 673.940 698.185 ;
        RECT 676.340 12.415 687.865 698.185 ;
  END
END accel_top
END LIBRARY

